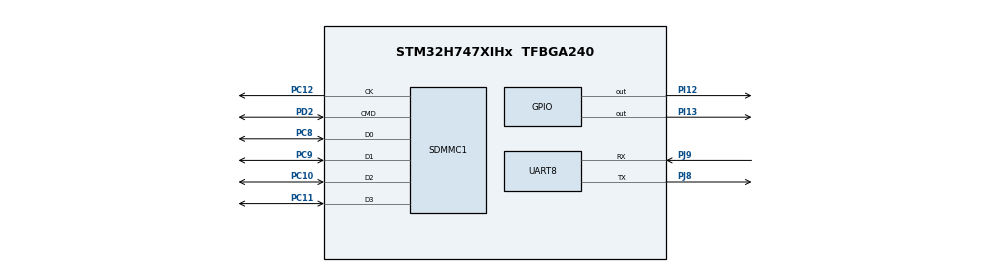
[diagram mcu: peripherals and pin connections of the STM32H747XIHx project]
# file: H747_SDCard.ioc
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CortexM4.IPs=BDMA,CORTEX_M4\:I,DEBUG,DMA,FATFS_M4\:I,FREERTOS_M4\:I,IWDG2\:I,MDMA,NVIC2\:I,OPENAMP_M4\:I,PDM2PCM_M4\:I,PWR,RCC,RESMGR_UTILITY,SYS_M4\:I,USB_DEVICE_M4\:I,USB_HOST_M4\:I,VREFBUF,WWDG2\:I
CortexM7.IPs=BDMA\:I,CORTEX_M7\:I,DEBUG\:I,DMA\:I,FATFS_M7\:I,FREERTOS_M7\:I,IWDG1\:I,MDMA\:I,NVIC1\:I,OPENAMP_M7\:I,PDM2PCM_M7\:I,PWR\:I,RCC\:I,RESMGR_UTILITY\:I,SYS\:I,USB_DEVICE_M7\:I,USB_HOST_M7\:I,VREFBUF\:I,WWDG1\:I,UART8\:I,SDMMC1\:I
CortexM7.Pins=PI12,PI13
FATFS_M7._MAX_SS=4096
Mcu.Family=STM32H7
Mcu.Name=STM32H747XIHx
Mcu.Package=TFBGA240
NVIC1.PriorityGroup=NVIC_PRIORITYGROUP_4
NVIC1.UART8_IRQn=true\:0\:0\:false\:false\:true\:true\:true
NVIC2.PriorityGroup=NVIC_PRIORITYGROUP_4
PC10.Mode=SD_4_bits_Wide_bus
PC10.PinAttribute=CortexM7
PC10.Signal=SDMMC1_D2
PC11.Mode=SD_4_bits_Wide_bus
PC11.PinAttribute=CortexM7
PC11.Signal=SDMMC1_D3
PC12.Mode=SD_4_bits_Wide_bus
PC12.PinAttribute=CortexM7
PC12.Signal=SDMMC1_CK
PC8.Mode=SD_4_bits_Wide_bus
PC8.PinAttribute=CortexM7
PC8.Signal=SDMMC1_D0
PC9.Mode=SD_4_bits_Wide_bus
PC9.PinAttribute=CortexM7
PC9.Signal=SDMMC1_D1
PD2.Mode=SD_4_bits_Wide_bus
PD2.PinAttribute=CortexM7
PD2.Signal=SDMMC1_CMD
PH0-OSC_IN\ (PH0).Mode=HSE-External-Oscillator
PH0-OSC_IN\ (PH0).PinAttribute=CortexM7
PH0-OSC_IN\ (PH0).Signal=RCC_OSC_IN
PH1-OSC_OUT\ (PH1).Mode=HSE-External-Oscillator
PH1-OSC_OUT\ (PH1).PinAttribute=CortexM7
PH1-OSC_OUT\ (PH1).Signal=RCC_OSC_OUT
PI12.PinAttribute=CortexM7
PI12.Signal=GPIO_Output
PI13.PinAttribute=CortexM7
PI13.Signal=GPIO_Output
PJ8.Mode=Asynchronous
PJ8.PinAttribute=CortexM7
PJ8.Signal=UART8_TX
PJ9.Mode=Asynchronous
PJ9.PinAttribute=CortexM7
PJ9.Signal=UART8_RX
ProjectManager.HeapSize=0x200
ProjectManager.StackSize=0x400
ProjectManager.TargetToolchain=STM32CubeIDE
RCC.ADCFreq_Value=400000000
RCC.APB1Freq_Value=50000000
RCC.APB2Freq_Value=50000000
RCC.APB3Freq_Value=50000000
RCC.APB4Freq_Value=50000000
RCC.CortexFreq_Value=50000000
RCC.D1CPRE=RCC_SYSCLK_DIV8
RCC.DIVM1=2
RCC.DIVM2=2
RCC.DIVM3=2
RCC.DIVN1=64
RCC.DIVN2=64
RCC.DIVN3=64
RCC.DIVQ1=16
RCC.DIVQ2=16
RCC.DIVQ3=16
RCC.DIVR2=16
RCC.HCLKFreq_Value=50000000
RCC.PLL2FRACN=0
RCC.PLL3FRACN=0
RCC.PLLFRACN=0
RCC.PLLSourceVirtual=RCC_PLLSOURCE_HSE
RCC.SYSCLKFreq_VALUE=400000000
RCC.SYSCLKSource=RCC_SYSCLKSOURCE_PLLCLK
RCC.USBFreq_Value=50000000
VP_FATFS_M7_VS_SDIO.Mode=SDIO
VP_SYS_M4_VS_Systick.Mode=SysTick
board=custom

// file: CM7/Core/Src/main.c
/* USER CODE BEGIN Header */
/**
  ******************************************************************************
  * @file           : main.c
  * @brief          : Main program body
  ******************************************************************************
  * @attention
  *
  * <h2><center>&copy; Copyright (c) 2020 STMicroelectronics.
  * All rights reserved.</center></h2>
  *
  * This software component is licensed by ST under BSD 3-Clause license,
  * the "License"; You may not use this file except in compliance with the
  * License. You may obtain a copy of the License at:
  *                        opensource.org/licenses/BSD-3-Clause
  *
  ******************************************************************************
  */
/* USER CODE END Header */
#include <stdio.h>
#include <string.h>
#include <stdarg.h>

#include "main.h"
#include "fatfs.h"

/* USER CODE BEGIN PD */

#define HSEM_ID_0 (0U) /* HW semaphore 0*/
/* USER CODE END PD */

/* USER CODE BEGIN PM */
#define HAL_TIMEOUT_VALUE 0xFFFFFFFF
#define countof(a) (sizeof(a) / sizeof(*(a)))

uint8_t UART1_TxBuffer[] = "I'm UART1\r\n";

SD_HandleTypeDef hsd1;

UART_HandleTypeDef huart8;

void SystemClock_Config(void);
static void MX_GPIO_Init(void);
static void MX_SDMMC1_SD_Init(void);
static void MX_UART8_Init(void);

int __io_putchar (int ch) {
	uint8_t c = ch;
	HAL_UART_Transmit(&huart8, &c, 1,1000);
	//HAL_UART_Transmit_IT(&huart1, (uint8_t*)&UART1_TxBuffer, countof(UART1_TxBuffer)-1);
	return ch;
}

int main(void)
{

	int32_t timeout;

	timeout = 0xFFFF;
	while((__HAL_RCC_GET_FLAG(RCC_FLAG_D2CKRDY) != RESET) && (timeout-- > 0));
	if ( timeout < 0 )
	{
	Error_Handler();
	}

	HAL_Init();

	SystemClock_Config();

	__HAL_RCC_HSEM_CLK_ENABLE();

	HAL_HSEM_FastTake(HSEM_ID_0);

	HAL_HSEM_Release(HSEM_ID_0,0);

	timeout = 0xFFFF;
	while((__HAL_RCC_GET_FLAG(RCC_FLAG_D2CKRDY) == RESET) && (timeout-- > 0));
	if ( timeout < 0 )
	{
	Error_Handler();
	}

	MX_GPIO_Init();
	MX_SDMMC1_SD_Init();
	MX_UART8_Init();
	MX_FATFS_Init();

	while (1)
	{
		printf("W5500_Init\n\r");
		//HAL_UART_Transmit(&huart8, (uint8_t*)&UART1_TxBuffer, countof(UART1_TxBuffer)-1, 1000);
		HAL_GPIO_TogglePin(GPIOI, GPIO_PIN_12);
		HAL_Delay(500);
	}
}

void HAL_UART_RxCpltCallback(UART_HandleTypeDef *huart)
{
	if(huart->Instance == huart8.Instance)
	{
		HAL_GPIO_TogglePin(GPIOI, GPIO_PIN_13);
	}
}

void SystemClock_Config(void)
{
  RCC_ClkInitTypeDef RCC_ClkInitStruct;
  RCC_OscInitTypeDef RCC_OscInitStruct;
  HAL_StatusTypeDef ret = HAL_OK;

  /*!< Supply configuration update enable */
  HAL_PWREx_ConfigSupply(PWR_DIRECT_SMPS_SUPPLY);

  /* The voltage scaling allows optimizing the power consumption when the device is
     clocked below the maximum system frequency, to update the voltage scaling value
     regarding system frequency refer to product datasheet.  */
  __HAL_PWR_VOLTAGESCALING_CONFIG(PWR_REGULATOR_VOLTAGE_SCALE1);

  while(!__HAL_PWR_GET_FLAG(PWR_FLAG_VOSRDY)) {}

  /* Enable HSE Oscillator and activate PLL with HSE as source */
  RCC_OscInitStruct.OscillatorType = RCC_OSCILLATORTYPE_HSE;
  RCC_OscInitStruct.HSEState = RCC_HSE_ON;
  RCC_OscInitStruct.HSIState = RCC_HSI_OFF;
  RCC_OscInitStruct.CSIState = RCC_CSI_OFF;
  RCC_OscInitStruct.PLL.PLLState = RCC_PLL_ON;
  RCC_OscInitStruct.PLL.PLLSource = RCC_PLLSOURCE_HSE;

  RCC_OscInitStruct.PLL.PLLM = 5;
  RCC_OscInitStruct.PLL.PLLN = 160;
  RCC_OscInitStruct.PLL.PLLFRACN = 0;
  RCC_OscInitStruct.PLL.PLLP = 2;
  RCC_OscInitStruct.PLL.PLLR = 2;
  RCC_OscInitStruct.PLL.PLLQ = 4;

  RCC_OscInitStruct.PLL.PLLVCOSEL = RCC_PLL1VCOWIDE;
  RCC_OscInitStruct.PLL.PLLRGE = RCC_PLL1VCIRANGE_2;
  ret = HAL_RCC_OscConfig(&RCC_OscInitStruct);
  if(ret != HAL_OK)
  {
    Error_Handler();
  }

/* Select PLL as system clock source and configure  bus clocks dividers */
  RCC_ClkInitStruct.ClockType = (RCC_CLOCKTYPE_SYSCLK | RCC_CLOCKTYPE_HCLK | RCC_CLOCKTYPE_D1PCLK1 | RCC_CLOCKTYPE_PCLK1 | \
                                 RCC_CLOCKTYPE_PCLK2  | RCC_CLOCKTYPE_D3PCLK1);

  RCC_ClkInitStruct.SYSCLKSource = RCC_SYSCLKSOURCE_PLLCLK;
  RCC_ClkInitStruct.SYSCLKDivider = RCC_SYSCLK_DIV1;
  RCC_ClkInitStruct.AHBCLKDivider = RCC_HCLK_DIV2;
  RCC_ClkInitStruct.APB3CLKDivider = RCC_APB3_DIV2;
  RCC_ClkInitStruct.APB1CLKDivider = RCC_APB1_DIV2;
  RCC_ClkInitStruct.APB2CLKDivider = RCC_APB2_DIV2;
  RCC_ClkInitStruct.APB4CLKDivider = RCC_APB4_DIV2;
  ret = HAL_RCC_ClockConfig(&RCC_ClkInitStruct, FLASH_LATENCY_4);
  if(ret != HAL_OK)
  {
    Error_Handler();
  }
    /*
  Note : The activation of the I/O Compensation Cell is recommended with communication  interfaces
          (GPIO, SPI, FMC, QSPI ...)  when  operating at  high frequencies(please refer to product datasheet)
          The I/O Compensation Cell activation  procedure requires :
        - The activation of the CSI clock
        - The activation of the SYSCFG clock
        - Enabling the I/O Compensation Cell : setting bit[0] of register SYSCFG_CCCSR

          To do this please uncomment the following code
  */

  /*
  __HAL_RCC_CSI_ENABLE() ;

  __HAL_RCC_SYSCFG_CLK_ENABLE() ;

  HAL_EnableCompensationCell();
  */
}

static void MX_SDMMC1_SD_Init(void)
{

  hsd1.Instance = SDMMC1;
  hsd1.Init.ClockEdge = SDMMC_CLOCK_EDGE_RISING;
  hsd1.Init.ClockPowerSave = SDMMC_CLOCK_POWER_SAVE_DISABLE;
  hsd1.Init.BusWide = SDMMC_BUS_WIDE_4B;
  hsd1.Init.HardwareFlowControl = SDMMC_HARDWARE_FLOW_CONTROL_DISABLE;
  hsd1.Init.ClockDiv = 0;
  hsd1.Init.TranceiverPresent = SDMMC_TRANSCEIVER_NOT_PRESENT;
  if (HAL_SD_Init(&hsd1) != HAL_OK)
  {
    Error_Handler();
  }

}

static void MX_UART8_Init(void)
{

  huart8.Instance = UART8;
  huart8.Init.BaudRate = 115200;
  huart8.Init.WordLength = UART_WORDLENGTH_8B;
  huart8.Init.StopBits = UART_STOPBITS_1;
  huart8.Init.Parity = UART_PARITY_NONE;
  huart8.Init.Mode = UART_MODE_TX_RX;
  huart8.Init.HwFlowCtl = UART_HWCONTROL_NONE;
  huart8.Init.OverSampling = UART_OVERSAMPLING_16;
  huart8.Init.OneBitSampling = UART_ONE_BIT_SAMPLE_DISABLE;
  huart8.Init.ClockPrescaler = UART_PRESCALER_DIV1;
  huart8.AdvancedInit.AdvFeatureInit = UART_ADVFEATURE_NO_INIT;
  if (HAL_UART_Init(&huart8) != HAL_OK)
  {
    Error_Handler();
  }
  if (HAL_UARTEx_SetTxFifoThreshold(&huart8, UART_TXFIFO_THRESHOLD_1_8) != HAL_OK)
  {
    Error_Handler();
  }
  if (HAL_UARTEx_SetRxFifoThreshold(&huart8, UART_RXFIFO_THRESHOLD_1_8) != HAL_OK)
  {
    Error_Handler();
  }
  if (HAL_UARTEx_DisableFifoMode(&huart8) != HAL_OK)
  {
    Error_Handler();
  }

}

static void MX_GPIO_Init(void)
{
  GPIO_InitTypeDef GPIO_InitStruct = {0};

  /* GPIO Ports Clock Enable */
  __HAL_RCC_GPIOC_CLK_ENABLE();
  __HAL_RCC_GPIOD_CLK_ENABLE();
  __HAL_RCC_GPIOI_CLK_ENABLE();
  __HAL_RCC_GPIOH_CLK_ENABLE();
  __HAL_RCC_GPIOJ_CLK_ENABLE();

  /*Configure GPIO pin Output Level */
  HAL_GPIO_WritePin(GPIOI, GPIO_PIN_12|GPIO_PIN_13, GPIO_PIN_RESET);

  /*Configure GPIO pins : PI12 PI13 */
  GPIO_InitStruct.Pin = GPIO_PIN_12|GPIO_PIN_13;
  GPIO_InitStruct.Mode = GPIO_MODE_OUTPUT_PP;
  GPIO_InitStruct.Pull = GPIO_NOPULL;
  GPIO_InitStruct.Speed = GPIO_SPEED_FREQ_LOW;
  HAL_GPIO_Init(GPIOI, &GPIO_InitStruct);

}

void Error_Handler(void)
{
}

/************************ (C) COPYRIGHT STMicroelectronics *****END OF FILE****/
